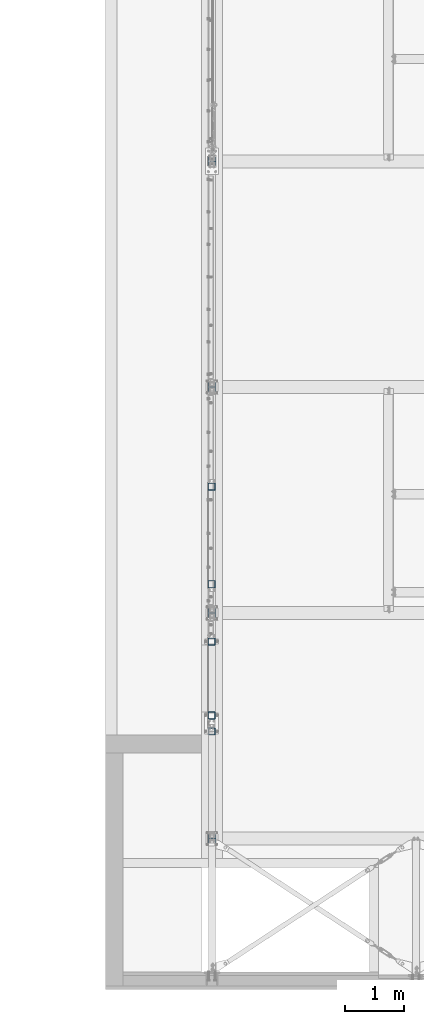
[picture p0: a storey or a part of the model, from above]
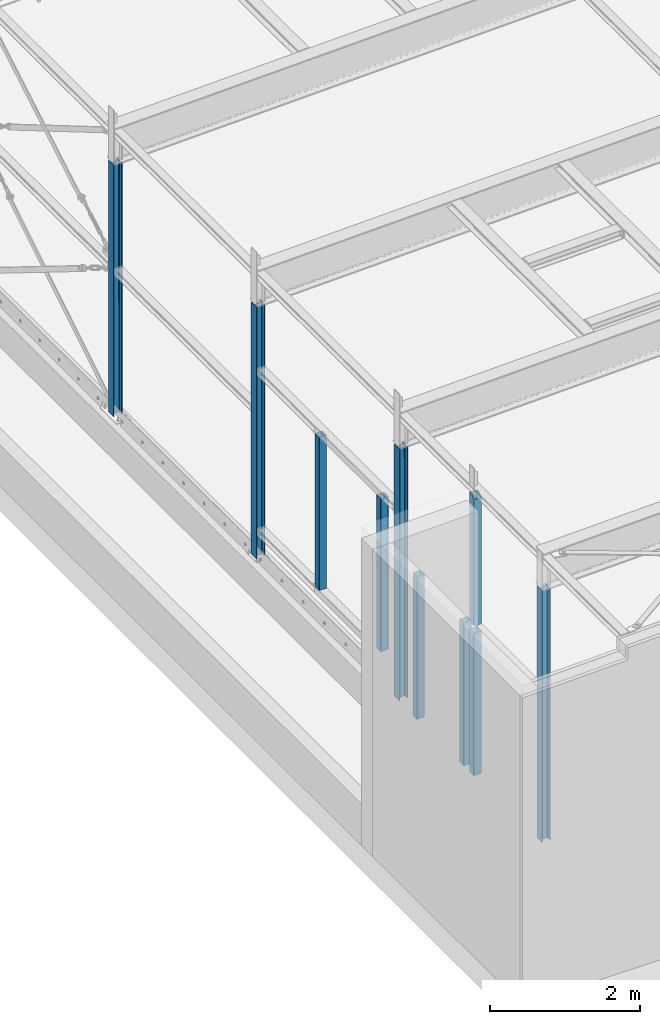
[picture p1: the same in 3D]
Properties of the parts of a building model (IFC2X3)

# File
Description: ViewDefinition[CoordinationView_V2.0]
File name: Technikzentrale auf Klinikdach Ostfildern_ifc2x3.ifc
Time: 2026-07-12T18:15:47
Organization: medius KLINIKEN gGmbH
Written by: IFC Toolkit 2.0.26.0
Made in: Advance Steel 2024

# IfcBuildingStorey, Default Storey
In: Struktur 1
Elevation: 0 mm

# IfcBeam: - (124)
In: Default Storey
Pset_BeamCommon - Reference: nicht definiert; Slope: 0 deg; IsExternal: no; LoadBearing: no
Name | Description = Section | Material | Span (mm) | SectionFamily
7 x - | HEA120 | S235JR | 3620 | HEA DIN18800-1
5 x - | HEA120 | S235JR | 3263.2 | HEA DIN18800-1
4 x - | HEA120 | S235JR | 2276 | HEA DIN18800-1
10 x - | RD14 | S235JR | 493.08 | Round nach DIN
2 x - | L250X90X10 | S235JR | 3660 | Angle_uneq DIN18800-1
- | L250X90X10 | S235JR | 3698.89 | Angle_uneq DIN18800-1
- | L250X90X10 | S235JR | 3208.02 | Angle_uneq DIN18800-1
2 x - | L250X90X10 | S235JR | 3290 | Angle_uneq DIN18800-1
- | L250X90X10 | S235JR | 3286.5 | Angle_uneq DIN18800-1
- | L250X90X10 | S235JR | 3166.13 | Angle_uneq DIN18800-1
2 x - | L250X90X10 | S235JR | 3140 | Angle_uneq DIN18800-1
- | L250X90X10 | S235JR | 3143.5 | Angle_uneq DIN18800-1
- | L250X90X10 | S235JR | 3300.16 | Angle_uneq DIN18800-1
- | L250X90X10 | S235JR | 284.316 | Angle_uneq DIN18800-1
- | L250X90X10 | S235JR | 955.853 | Angle_uneq DIN18800-1
- | L250X90X10 | S235JR | 1610 | Angle_uneq DIN18800-1
3 x - | L250X90X10 | S235JR | 3700 | Angle_uneq DIN18800-1
2 x - | Q120X4 | S235JR | 3290 | RHS_Sections_square_c nach DIN
4 x - | Q120X4 | S235JR | 3140 | RHS_Sections_square_c nach DIN
2 x - | HEA120 | S235JR | 263.998 | HEA DIN18800-1
2 x - | HEA160 | S235JR | 3775 | HEA DIN18800-1
2 x - | HEA160 | S235JR | 3778 | HEA DIN18800-1
2 x - | HEA160 | S235JR | 3258 | HEA DIN18800-1
- | HEA120 | S235JR | 3246.5 | HEA DIN18800-1
2 x - | HEA120 | S235JR | 3250 | HEA DIN18800-1
- | HEA120 | S235JR | 3268.5 | HEA DIN18800-1
- | HEA120 | S235JR | 3118.5 | HEA DIN18800-1
2 x - | HEA120 | S235JR | 3100 | HEA DIN18800-1
- | HEA120 | S235JR | 3126.13 | HEA DIN18800-1
2 x - | HEA120 | S235JR | 3235.25 | HEA DIN18800-1
- | HEA120 | S235JR | 3253.4 | HEA DIN18800-1
- | HEA120 | S235JR | 3253.42 | HEA DIN18800-1
- | HEA120 | S235JR | 3617 | HEA DIN18800-1
- | HEA120 | S235JR | 3096.5 | HEA DIN18800-1
- | HEA120 | S235JR | 3144.29 | HEA DIN18800-1
- | HEA120 | S235JR | 3635.16 | HEA DIN18800-1
- |  | C25/30 | 15699.1
- |  | C25/30 | 9838.25
3 x - | HEA120 | S235JR | 3264 | HEA DIN18800-1
9 x - | HEA120 | S235JR | 3784 | HEA DIN18800-1
- | HEA120 | S235JR | 2225.64 | HEA DIN18800-1
2 x - | HEA120 | S235JR | 3781 | HEA DIN18800-1
2 x - | HEA120 | S235JR | 3290.13 | HEA DIN18800-1
2 x - | HEA120 | S235JR | 3401.75 | HEA DIN18800-1
- |  | C25/30 | 14150
- |  | C25/30 | 16708.8
- |  | C25/30 | 24539.3
- |  | C25/30 | 17216.6
- |  | C25/30 | 1670
- | RHS100X80X4 | S235JR | 1585.5 | RHS_Sections_rectang_c nach DIN
- |  | C25/30 | 4320
- |  | C25/30 | 1769.64
- | L250X90X10 | S235JR | 334.998 | Angle_uneq DIN18800-1
- | L250X90X10 | S235JR | 1230 | Angle_uneq DIN18800-1
- | L250X90X10 | S235JR | 516.498 | Angle_uneq DIN18800-1
- |  | C25/30 | 12884.2
- |  | C25/30 | 10462.7
- |  | C25/30 | 24249.3
- |  | C25/30 | 15967.8
- |  | C25/30 | 1885
- |  | C25/30 | 3675
- | HEA 100 | S235JR | 9102 | HEA DIN18800-1
- | HEA 100 | S235JR | 7985 | HEA DIN18800-1
2 x - | HEA120 | S235JR | 3107.88 | HEA DIN18800-1
- | HEA120 | S235JR | 3489 | HEA DIN18800-1
- | HEA120 | S235JR | 2998.13 | HEA DIN18800-1
2 x - | HEA120 | S235JR | 3115.5 | HEA DIN18800-1
- | L250X90X10 | S235JR | 3293.5 | Angle_uneq DIN18800-1
- | L250X90X10 | S235JR | 3275.25 | Angle_uneq DIN18800-1
- | L250X90X10 | S235JR | 1490.25 | Angle_uneq DIN18800-1
- | L250X90X10 | S235JR | 3697 | Angle_uneq DIN18800-1

# IfcBuildingElementProxy: - (100)
In: Default Storey
Material: Kein

# IfcColumn: - (51)
In: Default Storey
Material: S235JR
Pset_ColumnCommon - Reference: nicht definiert; Slope: 0 deg; IsExternal: no; LoadBearing: no
Name | Description = Section | SectionFamily
15 x - | Q120X4 | RHS_Sections_square_c nach DIN
2 x - | FL55X6 | Flat nach DIN
24 x - | HEA140 | HEA DIN18800-1
6 x - | HEA 100 | HEA DIN18800-1
2 x - | RHS100X80X4 | RHS_Sections_rectang_c nach DIN
- | L100X10 | Angle_eq DIN18800-1
- | R120X60X4 | RHS_Sections_rectang_c nach DIN

# IfcColumn: AnchorBeam (10)
In: Default Storey
Material: S235JR
Pset_ColumnCommon - Reference: nicht definiert; Slope: 0 deg; IsExternal: no; LoadBearing: no
ProfileProperties - SectionFamily: IPE DIN18800-1
Name | Description = Section
7 x AnchorBeam | IPE180
3 x AnchorBeam | IPE100

# IfcMechanicalFastener: - (287)
In: Default Storey
Name | NominalDiameter (mm) | NominalLength (mm)
106 x  | 27 | 70
24 x  | 30 | 75
48 x  | 30 | 80
16 x  | 12 | 35
25 x  | 10 | 110
2 x  | 16 | 50
12 x  | 10 | 35
29 x  | 12 | 30
5 x  | 16 | 45
20 x  | 16 | 150

# IfcMechanicalFastener: Anchor_Bolt#1 (29)
In: Default Storey
NominalDiameter: 10 mm; NominalLength: 120 mm

# IfcMechanicalFastener: Bolt (33)
In: Default Storey
NominalDiameter: 12 mm
Name | NominalLength (mm)
22 x  | 60
4 x  | 50
2 x  | 55
5 x  | 40

# IfcMechanicalFastener: Bolt#1 (122)
In: Default Storey
Name | NominalDiameter (mm) | NominalLength (mm)
2 x  | 20 | 95
6 x  | 16 | 70
2 x  | 20 | 85
64 x  | 12 | 55
19 x  | 12 | 45
16 x  | 12 | 65
5 x  | 12 | 40
8 x  | 12 | 50

# IfcMechanicalFastener: Bolt#2 (143)
In: Default Storey
Name | NominalDiameter (mm) | NominalLength (mm)
2 x  | 20 | 95
6 x  | 16 | 70
2 x  | 20 | 85
66 x  | 12 | 55
7 x  | 12 | 45
16 x  | 12 | 65
22 x  | 12 | 60
12 x  | 12 | 50
10 x  | 12 | 40

# IfcMechanicalFastener: Bolt#3 (19)
In: Default Storey
NominalDiameter: 12 mm
Name | NominalLength (mm)
16 x  | 65
3 x  | 55

# IfcMechanicalFastener: Bolt#4 (19)
In: Default Storey
NominalDiameter: 12 mm
Name | NominalLength (mm)
16 x  | 65
3 x  | 55

# IfcMechanicalFastener: Bolt#5 (15)
In: Default Storey
NominalDiameter: 12 mm
Name | NominalLength (mm)
4 x  | 55
5 x  | 40
5 x  | 45
 | 50

# IfcMechanicalFastener: Bolt#6 (15)
In: Default Storey
NominalDiameter: 12 mm
Name | NominalLength (mm)
4 x  | 55
5 x  | 40
5 x  | 45
 | 50

# IfcMember: - (84)
In: Default Storey
Material: S235JR
Pset_MemberCommon - Reference: nicht definiert; Slope: 0 deg; IsExternal: no; LoadBearing: no
Name | Description = Section | Span (mm) | SectionFamily
8 x - | FL80X15 | 6675.66 | Flat nach DIN
- | FL80X15 | 6652.4 | Flat nach DIN
8 x - | FL80X15 | 3007.41 | Flat nach DIN
2 x - | FL80X15 | 6383.48 | Flat nach DIN
2 x - | FL80X15 | 6394.78 | Flat nach DIN
- | FL80X15 | 6655.32 | Flat nach DIN
8 x - | FL80X15 | 3695.56 | Flat nach DIN
6 x - | IPE600 | 13937.3 | IPE DIN18800-1
2 x - | IPE600 | 12899.4 | IPE DIN18800-1
- | IPE270 | 13927.4 | IPE DIN18800-1
5 x - | HEA120 | 1566.47 | HEA DIN18800-1
- | HEA120 | 1563.97 | HEA DIN18800-1
6 x - | HEA160 | 1440 | HEA DIN18800-1
- | FL80X15 | 6443.73 | Flat nach DIN
2 x - | FL80X15 | 3129.68 | Flat nach DIN
- | FL80X15 | 1419.96 | Flat nach DIN
- | FL80X15 | 1420.03 | Flat nach DIN
2 x - | FL80X15 | 3020.87 | Flat nach DIN
2 x - | FL80X15 | 2965.29 | Flat nach DIN
2 x - | FL80X15 | 3362.76 | Flat nach DIN
2 x - | FL80X15 | 3441.61 | Flat nach DIN
2 x - | FL80X15 | 3147.92 | Flat nach DIN
2 x - | FL80X15 | 3314.67 | Flat nach DIN
2 x - | FL80X15 | 2758.09 | Flat nach DIN
2 x - | FL80X15 | 2909.94 | Flat nach DIN
- | FL80X15 | 2884.59 | Flat nach DIN
- | FL80X15 | 2923.8 | Flat nach DIN
- | FL80X15 | 3069.82 | Flat nach DIN
- | FL80X15 | 3069.79 | Flat nach DIN
- | FL80X15 | 2946.65 | Flat nach DIN
- | FL80X15 | 2988.21 | Flat nach DIN
2 x - | FL80X15 | 3066.86 | Flat nach DIN
- | HEA500 | 15635.4 | HEA DIN18800-1
2 x - | HEA220 | 6234.64 | HEA DIN18800-1
- | FL80X15 | 6440.57 | Flat nach DIN

# IfcPlate: - (235)
In: Default Storey
Description: -
Pset_PlateCommon - Reference: nicht definiert; IsExternal: no; LoadBearing: no
Name | Material
124 x - | S235JR 15 mm
32 x - | S235JR 8 mm
53 x - | S235JR 10 mm
7 x - | S235JR 6 mm
13 x - | S235JR 20 mm
6 x - | S235JR 12 mm

# IfcPlate: Baseplate (37)
In: Default Storey
Description: -
Pset_PlateCommon - Reference: nicht definiert; IsExternal: no; LoadBearing: no
Name | Material
8 x Baseplate | S235JR 10 mm
29 x Baseplate | S235JR 15 mm

# IfcPlate: Coverplate (25)
In: Default Storey
Description: -; Material: S235JR 10 mm
Pset_PlateCommon - Reference: nicht definiert; IsExternal: no; LoadBearing: no

# IfcPlate: Endplate (103)
In: Default Storey
Description: -
Pset_PlateCommon - Reference: nicht definiert; IsExternal: no; LoadBearing: no
Name | Material
11 x Endplate | S235JR 10 mm
5 x Endplate | S235JR 15 mm
63 x Endplate | S235JR 12 mm
24 x Endplate | S235JR 20 mm

# IfcPlate: Endplate#1 (76)
In: Default Storey
Description: -
Pset_PlateCommon - Reference: nicht definiert; IsExternal: no; LoadBearing: no
Name | Material
2 x Endplate#1 | S235JR 30 mm
6 x Endplate#1 | S235JR 20 mm
2 x Endplate#1 | S235JR 25 mm
59 x Endplate#1 | S235JR 15 mm
7 x Endplate#1 | S235JR 12 mm

# IfcPlate: Endplate#2 (11)
In: Default Storey
Description: -
Pset_PlateCommon - Reference: nicht definiert; IsExternal: no; LoadBearing: no
Name | Material
2 x Endplate#2 | S235JR 30 mm
6 x Endplate#2 | S235JR 20 mm
2 x Endplate#2 | S235JR 25 mm
Endplate#2 | S235JR 15 mm

# IfcPlate: LugPlate#1 (6)
In: Default Storey
Description: -; Material: S235JR 15 mm
Pset_PlateCommon - Reference: nicht definiert; IsExternal: no; LoadBearing: no

# IfcPlate: LugPlate#2 (6)
In: Default Storey
Description: -; Material: S235JR 15 mm
Pset_PlateCommon - Reference: nicht definiert; IsExternal: no; LoadBearing: no

# IfcPlate: Stiffener#1 (7)
In: Default Storey
Description: -; Material: S235JR 10 mm
Pset_PlateCommon - Reference: nicht definiert; IsExternal: no; LoadBearing: no

# IfcPlate: Stiffener#2 (41)
In: Default Storey
Description: -; Material: S235JR 10 mm
Pset_PlateCommon - Reference: nicht definiert; IsExternal: no; LoadBearing: no

# IfcPlate: T-plate (63)
In: Default Storey
Description: -
Pset_PlateCommon - Reference: nicht definiert; IsExternal: no; LoadBearing: no
Name | Material
56 x T-plate | S235JR 15 mm
7 x T-plate | S235JR 12 mm

# IfcSlab: - (3)
In: Default Storey
Description: -
Pset_SlabCommon - Reference: nicht definiert; IsExternal: no; LoadBearing: no; Combustible: no; Compartmentation: no; PitchAngle: 0 deg
Name | Material
2 x - | C25/30 200 mm
- | C25/30 400 mm

# IfcWall: - (17)
In: Default Storey
Description: -
Pset_WallCommon - Reference: nicht definiert; Combustible: no; IsExternal: no; ExtendToStructure: no; LoadBearing: no; Compartmentation: no
Name | Material
8 x - | C25/30 60 mm
4 x - | C25/30 300 mm
2 x - | C25/30 180 mm
- | C25/30 130 mm
2 x - | C25/30 400 mm
